VERSION 5.7 ;
  NOWIREEXTENSIONATPIN ON ;
  DIVIDERCHAR "/" ;
  BUSBITCHARS "[]" ;
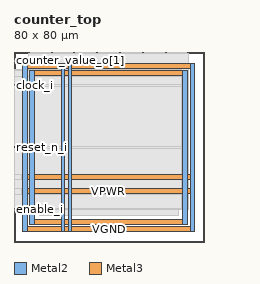
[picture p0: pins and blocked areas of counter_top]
MACRO counter_top
  CLASS BLOCK ;
  FOREIGN counter_top ;
  ORIGIN 0.000 0.000 ;
  SIZE 80.000 BY 80.000 ;
  PIN VGND
    DIRECTION INOUT ;
    USE GROUND ;
    PORT
      LAYER Metal2 ;
        RECT 3.560 4.340 5.560 75.040 ;
    END
    PORT
      LAYER Metal2 ;
        RECT 74.120 4.340 76.120 75.040 ;
    END
    PORT
      LAYER Metal3 ;
        RECT 3.560 4.340 76.120 6.340 ;
    END
    PORT
      LAYER Metal3 ;
        RECT 3.560 73.040 76.120 75.040 ;
    END
    PORT
      LAYER Metal2 ;
        RECT 23.060 4.340 24.060 75.040 ;
    END
    PORT
      LAYER Metal3 ;
        RECT 3.560 26.340 76.120 28.340 ;
    END
  END VGND
  PIN VPWR
    DIRECTION INOUT ;
    USE POWER ;
    PORT
      LAYER Metal2 ;
        RECT 6.560 7.340 8.560 72.040 ;
    END
    PORT
      LAYER Metal2 ;
        RECT 71.120 7.340 73.120 72.040 ;
    END
    PORT
      LAYER Metal3 ;
        RECT 6.560 7.340 73.120 9.340 ;
    END
    PORT
      LAYER Metal3 ;
        RECT 6.560 70.040 73.120 72.040 ;
    END
    PORT
      LAYER Metal2 ;
        RECT 20.060 4.340 21.060 75.040 ;
    END
    PORT
      LAYER Metal3 ;
        RECT 3.560 20.340 76.120 22.340 ;
    END
  END VPWR
  PIN clock_i
    DIRECTION INPUT ;
    USE SIGNAL ;
    ANTENNAGATEAREA 0.725400 ;
    PORT
      LAYER Metal3 ;
        RECT 0.000 65.740 0.400 66.140 ;
    END
  END clock_i
  PIN counter_value_o[0]
    DIRECTION OUTPUT ;
    USE SIGNAL ;
    ANTENNADIFFAREA 0.708600 ;
    PORT
      LAYER Metal2 ;
        RECT 6.040 79.600 6.440 80.000 ;
    END
  END counter_value_o[0]
  PIN counter_value_o[1]
    DIRECTION OUTPUT ;
    USE SIGNAL ;
    ANTENNADIFFAREA 0.708600 ;
    PORT
      LAYER Metal2 ;
        RECT 15.640 79.600 16.040 80.000 ;
    END
  END counter_value_o[1]
  PIN counter_value_o[2]
    DIRECTION OUTPUT ;
    USE SIGNAL ;
    ANTENNADIFFAREA 0.708600 ;
    PORT
      LAYER Metal2 ;
        RECT 25.240 79.600 25.640 80.000 ;
    END
  END counter_value_o[2]
  PIN counter_value_o[3]
    DIRECTION OUTPUT ;
    USE SIGNAL ;
    ANTENNADIFFAREA 0.708600 ;
    PORT
      LAYER Metal2 ;
        RECT 34.840 79.600 35.240 80.000 ;
    END
  END counter_value_o[3]
  PIN counter_value_o[4]
    DIRECTION OUTPUT ;
    USE SIGNAL ;
    ANTENNADIFFAREA 0.708600 ;
    PORT
      LAYER Metal2 ;
        RECT 44.440 79.600 44.840 80.000 ;
    END
  END counter_value_o[4]
  PIN counter_value_o[5]
    DIRECTION OUTPUT ;
    USE SIGNAL ;
    ANTENNADIFFAREA 0.708600 ;
    PORT
      LAYER Metal2 ;
        RECT 54.040 79.600 54.440 80.000 ;
    END
  END counter_value_o[5]
  PIN counter_value_o[6]
    DIRECTION OUTPUT ;
    USE SIGNAL ;
    ANTENNADIFFAREA 0.708600 ;
    PORT
      LAYER Metal2 ;
        RECT 63.640 79.600 64.040 80.000 ;
    END
  END counter_value_o[6]
  PIN counter_value_o[7]
    DIRECTION OUTPUT ;
    USE SIGNAL ;
    ANTENNADIFFAREA 0.708600 ;
    PORT
      LAYER Metal2 ;
        RECT 73.240 79.600 73.640 80.000 ;
    END
  END counter_value_o[7]
  PIN enable_i
    DIRECTION INPUT ;
    USE SIGNAL ;
    ANTENNAGATEAREA 0.180700 ;
    PORT
      LAYER Metal3 ;
        RECT 0.000 13.660 0.400 14.060 ;
    END
  END enable_i
  PIN reset_n_i
    DIRECTION INPUT ;
    USE SIGNAL ;
    ANTENNAGATEAREA 0.180700 ;
    PORT
      LAYER Metal3 ;
        RECT 0.000 39.700 0.400 40.100 ;
    END
  END reset_n_i
  OBS
      LAYER GatPoly ;
        RECT 10.560 11.190 69.120 68.190 ;
      LAYER Metal1 ;
        RECT 10.560 11.120 69.120 68.260 ;
      LAYER Metal2 ;
        RECT 6.650 79.390 15.430 79.600 ;
        RECT 16.250 79.390 25.030 79.600 ;
        RECT 25.850 79.390 34.630 79.600 ;
        RECT 35.450 79.390 44.230 79.600 ;
        RECT 45.050 79.390 53.830 79.600 ;
        RECT 54.650 79.390 63.430 79.600 ;
        RECT 64.250 79.390 73.030 79.600 ;
        RECT 6.135 75.250 73.540 79.390 ;
        RECT 6.135 72.250 19.850 75.250 ;
        RECT 6.135 13.715 6.350 72.250 ;
        RECT 8.770 13.715 19.850 72.250 ;
        RECT 21.270 13.715 22.850 75.250 ;
        RECT 24.270 72.250 73.540 75.250 ;
        RECT 24.270 13.715 70.910 72.250 ;
        RECT 73.330 13.715 73.540 72.250 ;
      LAYER Metal3 ;
        RECT 0.400 72.250 70.705 72.760 ;
        RECT 0.400 69.830 6.350 72.250 ;
        RECT 0.400 66.350 70.705 69.830 ;
        RECT 0.610 65.530 70.705 66.350 ;
        RECT 0.400 40.310 70.705 65.530 ;
        RECT 0.610 39.490 70.705 40.310 ;
        RECT 0.400 28.550 70.705 39.490 ;
        RECT 0.400 26.130 3.350 28.550 ;
        RECT 0.400 22.550 70.705 26.130 ;
        RECT 0.400 20.130 3.350 22.550 ;
        RECT 0.400 14.270 70.705 20.130 ;
        RECT 0.610 13.760 70.705 14.270 ;
  END
END counter_top
END LIBRARY

